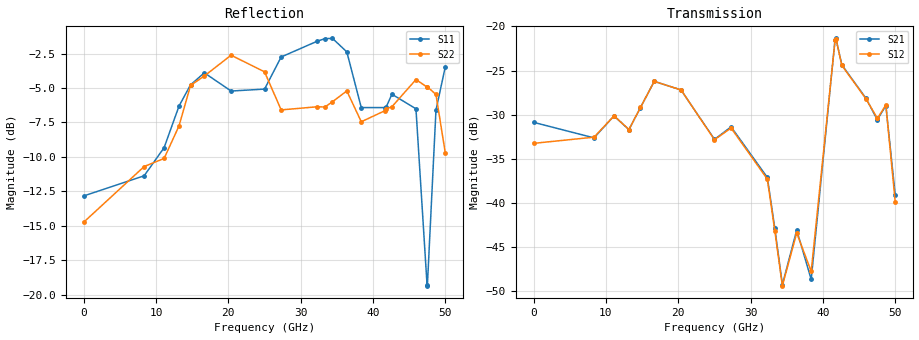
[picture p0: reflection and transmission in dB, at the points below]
!Keysight Technologies,N5245B,MY58422270,A.16.20.02
!Date: Thursday, March 05, 2026 01:43:59
!Correction: S11(C  2-Port  )
!S21(C  2-Port  )
!S12(C  2-Port  )
!S22(C  2-Port  )
!S2P File: Measurements: S11, S21, S12, S22:
# Hz S  dB  R 50
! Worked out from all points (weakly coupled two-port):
!   3201 points, 10 MHz to 50 GHz, reference 50 ohm
!   highest |S21| = -21.35 dB at 41.8 GHz (marker M1); lowest = -49.3 dB at 34.39 GHz (marker M2)
!   lowest |S11| = -19.3 dB at 47.52 GHz (marker M3), VSWR 1.24, Z = 45.1 + j9.07 ohm
!   |S11| at or under -10 dB: start of sweep to 10.03 GHz; 11.36 GHz to 11.93 GHz (575.7 MHz wide, 4.94 % of centre); 46.69 GHz to 48.23 GHz (1.548 GHz wide, 3.26 % of centre)
!   |S22| runs from -18.4 to -2.5 dB; largest |S21 - S12| = 0.0076
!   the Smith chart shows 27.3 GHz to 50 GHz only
!   S11 on the Smith chart (normalised r, x): 27.3 GHz: 0.18, +0.37; 32.32 GHz: 0.42, +1.86; 36.38 GHz: 2.35, -3.33; 42.61 GHz: 0.93, -1.22; 47.47 GHz: 0.87, +0.16; 50 GHz: 0.62, -1.38
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1e7  -12.83 -4.0  -30.88 2.1  -33.26 -5.6  -14.73 38.9
8.352081e9  -11.37 174.9  -32.64 33.8  -32.56 33.6  -10.70 -178.8
1.111715e10  -9.33 107.2  -30.15 -60.0  -30.14 -60.1  -10.11 82.5
1.317924e10  -6.31 63.0  -31.71 -110.6  -31.69 -110.2  -7.75 -23.9
1.477267e10  -4.77 12.3  -29.20 -143.6  -29.19 -143.6  -4.81 -91.7
1.667854e10  -3.90 -43.9  -26.23 160.1  -26.23 159.9  -4.13 -142.7
2.038092e10  -5.22 -121.2  -27.20 41.7  -27.20 41.3  -2.62 153.6
2.5005e10  -5.08 -178.9  -32.81 -65.2  -32.85 -65.7  -3.83 71.1
2.730142e10  -2.75 138.4  -31.39 -115.2  -31.52 -116.5  -6.59 30.9
3.231604e10  -1.60 54.6  -37.13 47.3  -37.32 45.5  -6.36 -106.1
3.334708e10  -1.42 36.0  -42.89 4.0  -43.19 0.5  -6.38 -129.8
3.439375e10  -1.40 17.3  -49.29 -107.9  -49.41 -94.5  -6.00 -152.7
3.637772e10  -2.38 -23.1  -43.10 117.7  -43.43 112.2  -5.21 169.2
3.837732e10  -6.42 -22.4  -48.70 -98.1  -47.79 44.5  -7.45 137.7
4.167354e10  -6.42 -53.0  -21.51 -54.8  -21.58 -55.1  -6.64 112.3
4.179852e10  -6.41 -53.0  -21.35 -66.6  -21.37 -66.3  -6.52 111.3
4.261085e10  -5.45 -61.1  -24.35 -120.4  -24.42 -120.3  -6.36 107.3
4.593831e10  -6.51 -117.1  -28.13 46.8  -28.20 46.1  -4.39 62.5
4.746926e10  -19.26 123.7  -30.51 -9.9  -30.33 -7.3  -4.93 43.6
4.751612e10  -19.34 112.9  -30.57 -10.4  -30.44 -7.9  -4.91 43.1
4.870338e10  -6.61 -21.3  -28.98 -84.6  -28.91 -84.6  -5.47 20.5
5e10  -3.45 -65.0  -39.15 -126.8  -39.93 -149.1  -9.73 7.2
